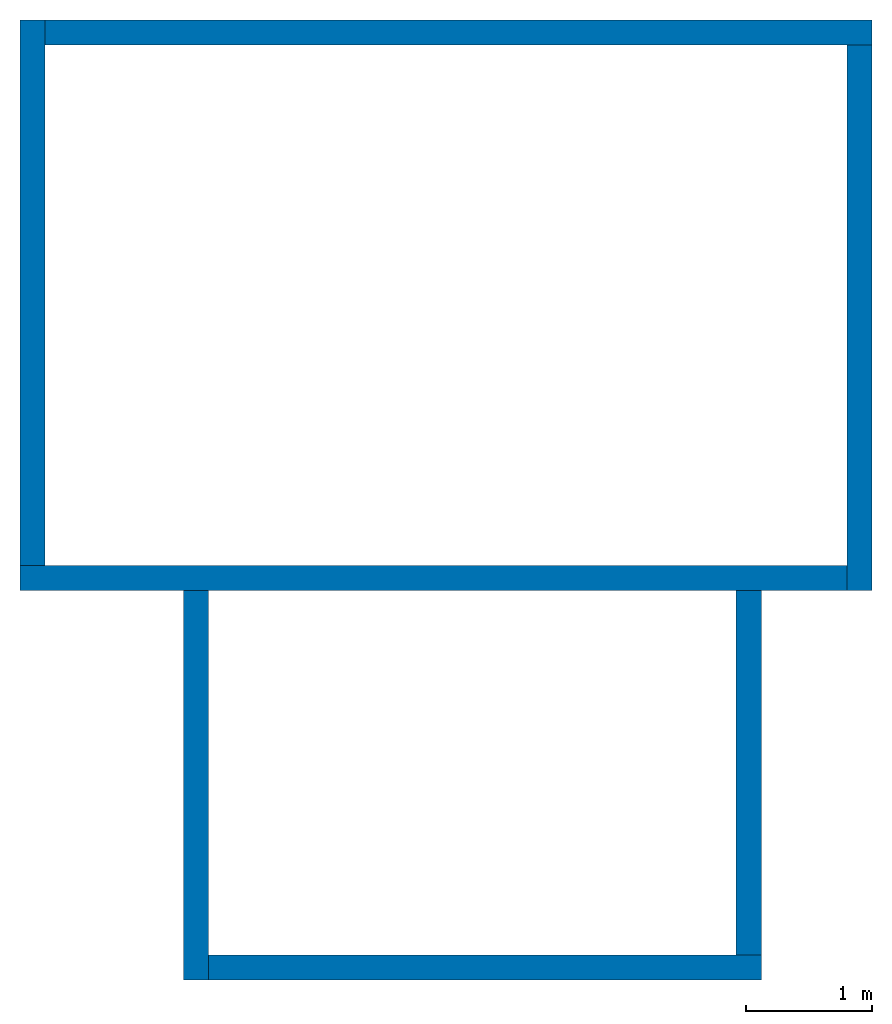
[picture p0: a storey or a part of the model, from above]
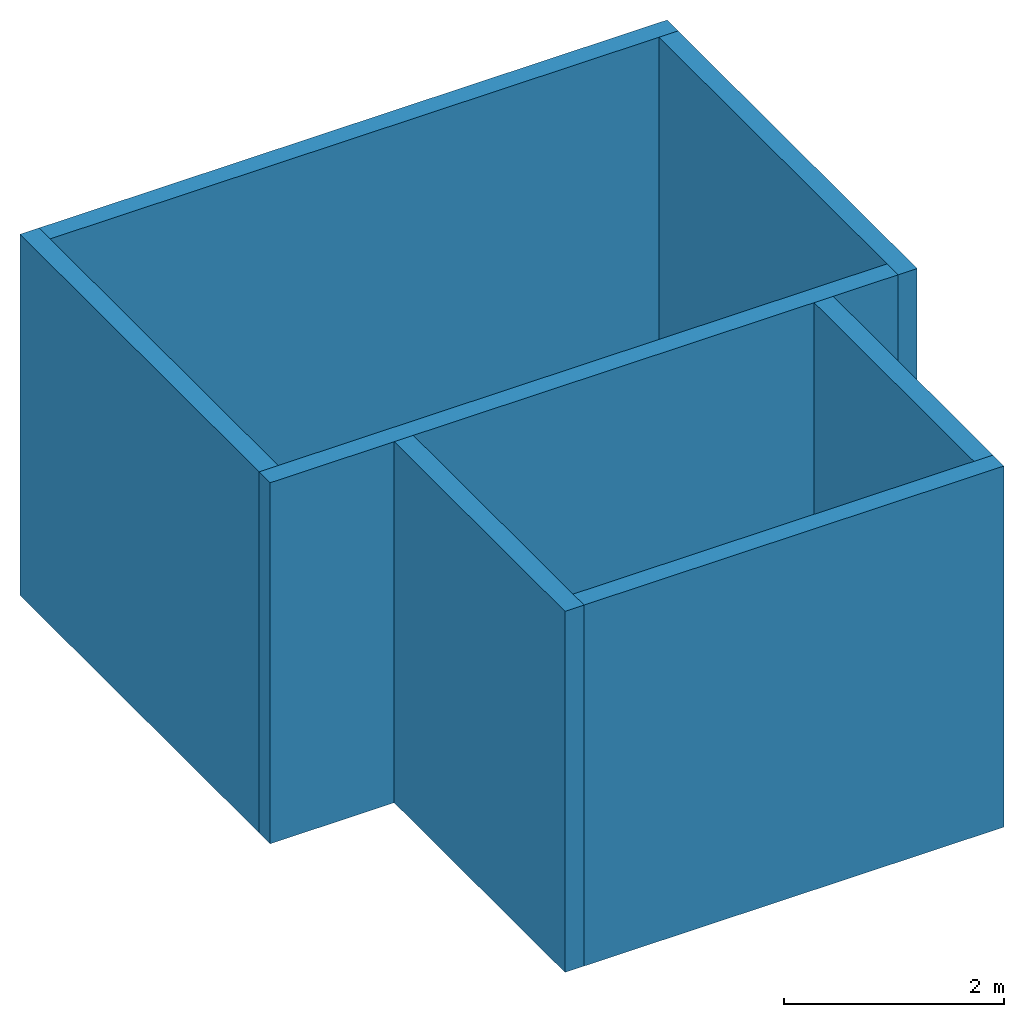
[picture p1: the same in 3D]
Properties of the parts of a building model (IFC2X3)

# File
Description: ViewDefinition [CoordinationView, QuantityTakeOffAddOnView]
Time: 2014-07-04T12:20:01
Written by: The EXPRESS Data Manager Version 5.01.0100.02.64mod : 6 Jun 2012
Made in: 20130308_1515(x64) - Exporter 2014.0.2013.0308 - Alternate UI 2.10.2.0
Comment: STEP Physical File produced by: The EXPRESS Data Manager Version 5.01.0100.02.64mod : 6 Jun 2012 * Module: EDMstepFileFactory/EDMstandAlone * Creation date: Fri Jul 04 12:20:01 2014 * Host: MDRLAPTOP-PC * Database: C:\Users\MDRLAP~1\AppData\Local\Temp\{70EB86A7-737F-4F98-A419-E65C16EC97FB}\ifc * Database version: 5507 * Database creation date: Fri Jul 04 12:20:01 2014 * Schema: IFC2X3 * Model: DataRepository.ifc * Model creation date: Fri Jul 04 12:20:01 2014 * Header model: DataRepository.ifc_HeaderModel * Header model creation date: Fri Jul 04 12:20:01 2014 * EDMuser: sdai-user * EDMgroup: sdai-group * License ID and type: 5605 : Permanent license. Expiry date: * EDMstepFileFactory options: 020000

# IfcProject
LongName: D:\MdR Advies\Google Drive\001 - Overige werkzaamheden\AU2013\class\files\testfile_ClassificationCode2.ifc

# IfcSite, Default
RefLatitude: 42, 24, 53, 508911; RefLongitude: -71, -15, -29, -58837; RefElevation: 0 mm

# IfcBuilding
Pset_BuildingCommon - NumberOfStoreys: 1

# IfcBuildingStorey, Level 1
LongName: Level 1; Elevation: 0 mm

# IfcSpace (2)
In: Level 1
LongName: Room; InteriorOrExteriorSpace: INTERNAL
BaseQuantities - Height: 2438.4 mm
Name | GrossFloorArea (m2) | GrossPerimeter (mm) | Reference
1 | 26.4132 | 21040 | Room 1
2 | 12.18 | 14200 | Room 2

# IfcWallStandardCase: Basic Wall:Wall 1 (7)
In: Level 1
Type - PredefinedType: STANDARD; Material: Default Wall 200 mm
BaseQuantities - Height: 4000 mm; Width: 200 mm; GrossVolume: 0.0283168 m3
Pset_WallCommon - Reference: Wall 1; LoadBearing: no; ExtendToStructure: no; IsExternal: yes
Name (Basic Wall:Wall 1:...) | Length (mm) | GrossSideArea (m2) | GrossFootprintArea (m2)
2277 | 6580 | 26.32 | 1.316
2278 | 4340 | 17.36 | 0.868
2279 | 6580 | 26.32 | 1.316
2280 | 4340 | 17.36 | 0.868
2354 | 3100 | 12.4 | 0.62
2388 | 4400 | 17.6 | 0.88
2422 | 3100 | 11.6 | 0.58
